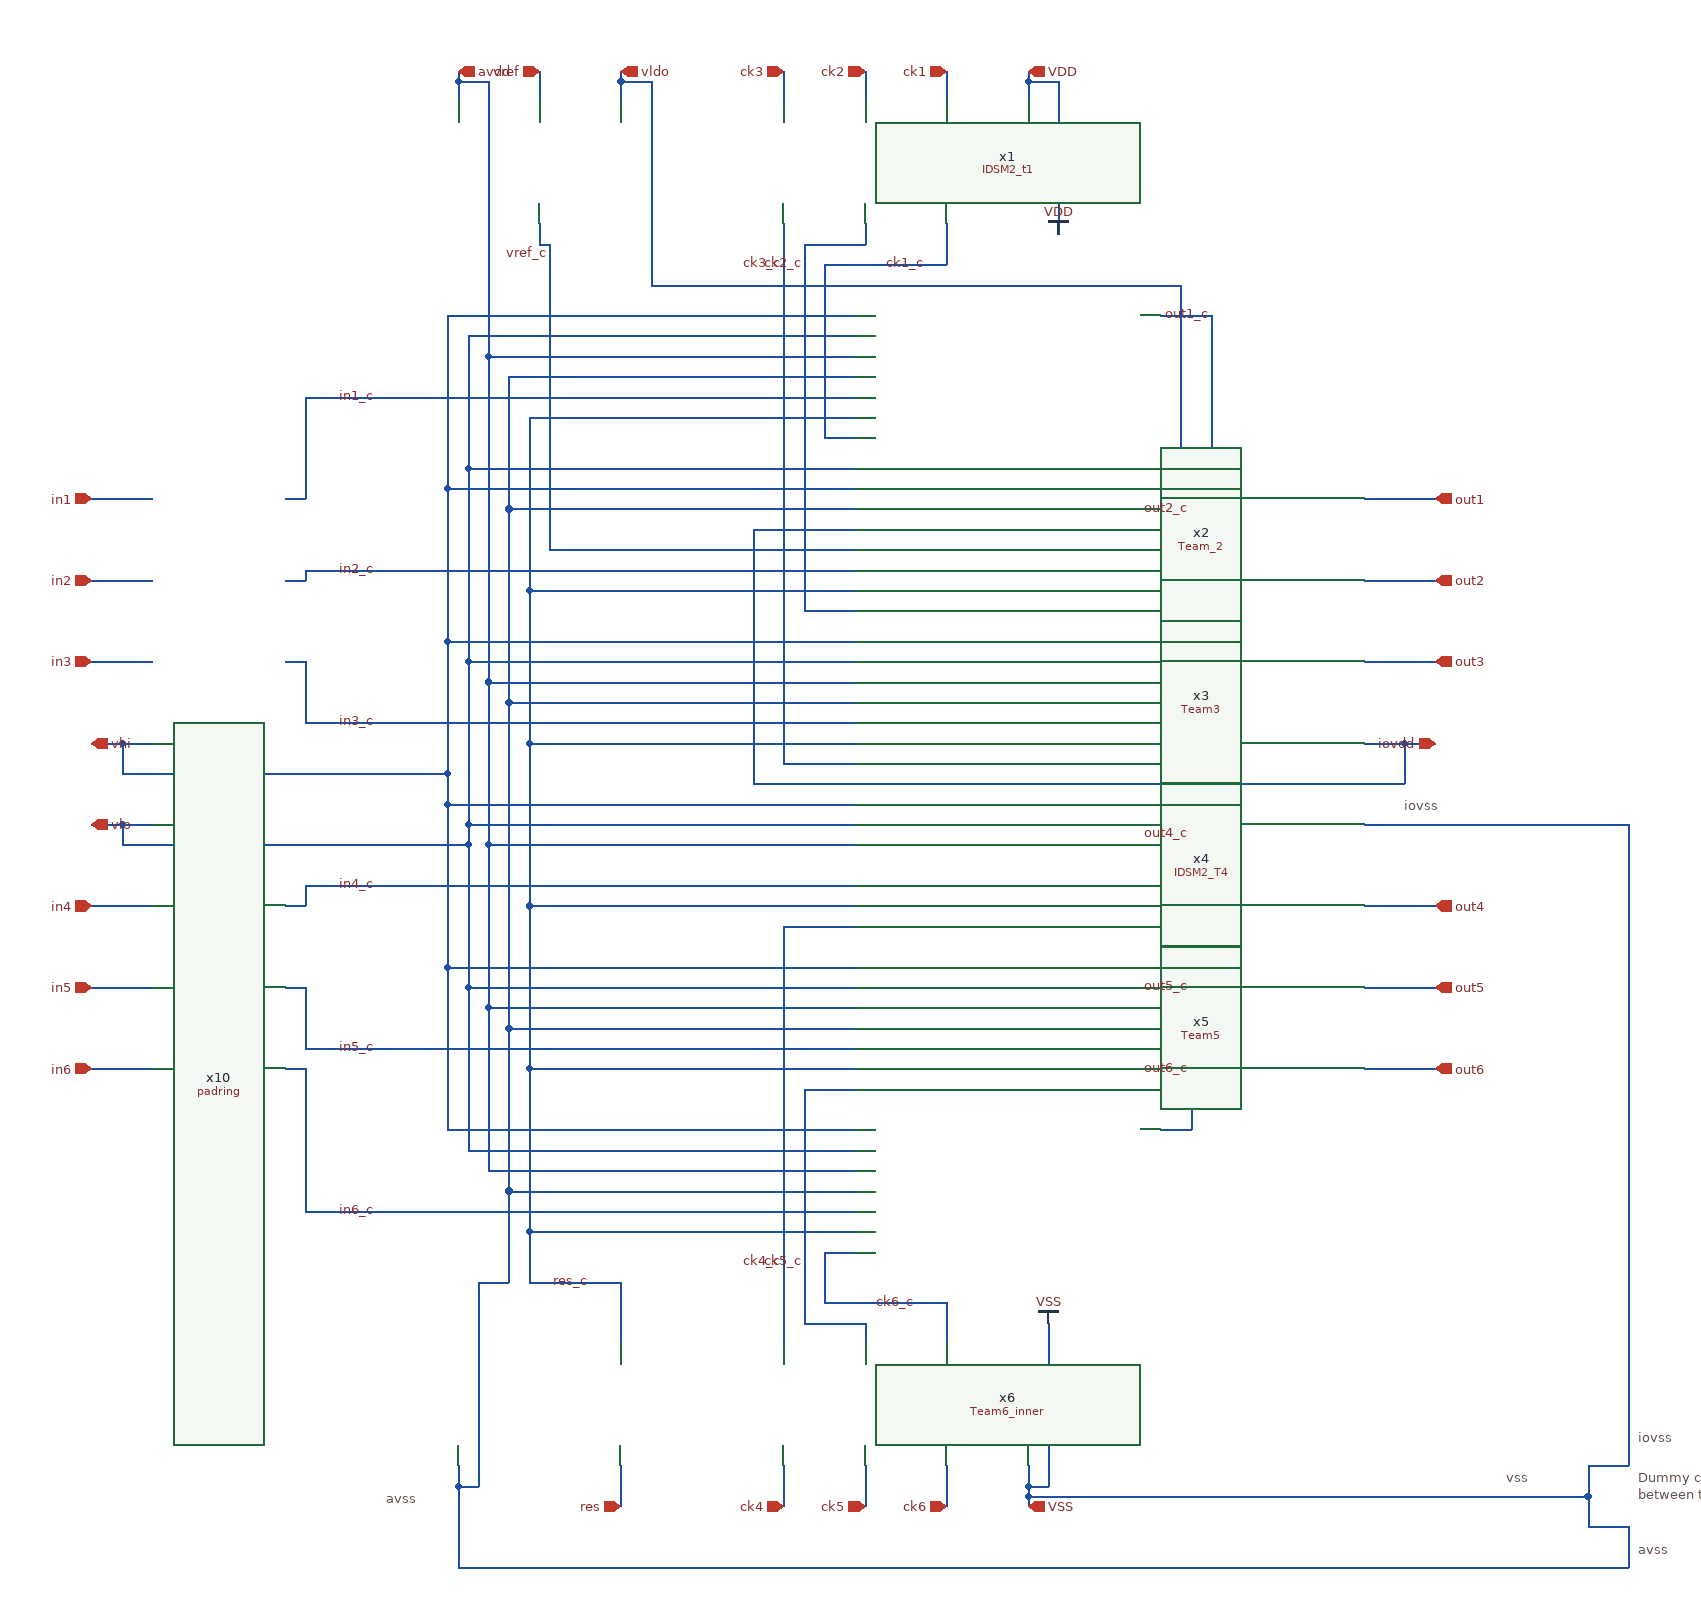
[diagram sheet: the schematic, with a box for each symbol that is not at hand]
v {xschem version=3.4.5 file_version=1.2
}
G {}
K {}
V {}
S {}
E {}
T {avss} 1570 -110 0 0 0.4 0.4 {}
T {iovss} 1340 -840 0 0 0.4 0.4 {}
T {Dummy connections to please LVS (no metal connection 
between these 3 nets, only soft short through substrate)} 1570 -180 0 0 0.4 0.4 {}
T {avss} 340 -160 0 0 0.4 0.4 {}
T {iovss} 1570 -220 0 0 0.4 0.4 {}
T {vss} 1440 -180 0 0 0.4 0.4 {}
N 1150 -1310 1150 -1130 {
lab=out1_c}
N 1130 -1050 1180 -1050 {
lab=out2_c}
N 1150 -970 1180 -970 {
lab=out3_c}
N 1150 -990 1150 -970 {
lab=out3_c}
N 1130 -830 1130 -730 {
lab=out4_c}
N 1130 -730 1180 -730 {
lab=out4_c}
N 1130 -650 1180 -650 {
lab=out5_c}
N 1130 -670 1130 -650 {
lab=out5_c}
N 1130 -570 1130 -510 {
lab=out6_c}
N 1130 -570 1180 -570 {
lab=out6_c}
N 400 -670 400 -510 {
lab=vhi}
N 420 -650 420 -490 {
lab=vlo}
N 440 -630 440 -470 {
lab=avdd}
N 460 -610 460 -450 {
lab=VSS}
N 480 -410 480 -360 {
lab=res_c}
N 80 -890 110 -890 {
lab=vhi}
N 80 -810 110 -810 {
lab=vlo}
N 420 -490 800 -490 {
lab=vlo}
N 400 -510 800 -510 {
lab=vhi}
N 440 -470 800 -470 {
lab=avdd}
N 460 -450 800 -450 {
lab=VSS}
N 410 -160 410 -80 {
lab=VSS}
N 410 -160 430 -160 {
lab=VSS}
N 410 -180 410 -160 {
lab=VSS}
N 430 -360 430 -160 {
lab=VSS}
N 430 -360 460 -360 {
lab=VSS}
N 460 -450 460 -360 {
lab=VSS}
N 570 -360 570 -300 {
lab=res_c}
N 480 -360 570 -360 {
lab=res_c}
N 480 -410 800 -410 {
lab=res_c}
N 480 -570 480 -410 {
lab=res_c}
N 260 -430 800 -430 {
lab=in6_c}
N 260 -570 260 -430 {
lab=in6_c}
N 240 -570 260 -570 {
lab=in6_c}
N 480 -570 800 -570 {
lab=res_c}
N 480 -730 480 -570 {
lab=res_c}
N 460 -610 800 -610 {
lab=VSS}
N 440 -630 800 -630 {
lab=avdd}
N 420 -650 800 -650 {
lab=vlo}
N 400 -670 800 -670 {
lab=vhi}
N 400 -830 400 -670 {
lab=vhi}
N 480 -730 800 -730 {
lab=res_c}
N 440 -790 440 -630 {
lab=avdd}
N 420 -790 420 -650 {
lab=vlo}
N 420 -810 800 -810 {
lab=vlo}
N 440 -790 800 -790 {
lab=avdd}
N 400 -830 800 -830 {
lab=vhi}
N 400 -860 400 -830 {
lab=vhi}
N 80 -790 420 -790 {
lab=vlo}
N 420 -810 420 -790 {
lab=vlo}
N 80 -810 80 -790 {
lab=vlo}
N 260 -590 800 -590 {
lab=in5_c}
N 260 -650 260 -590 {
lab=in5_c}
N 240 -650 260 -650 {
lab=in5_c}
N 260 -750 800 -750 {
lab=in4_c}
N 260 -750 260 -730 {
lab=in4_c}
N 240 -730 260 -730 {
lab=in4_c}
N 480 -890 480 -730 {
lab=res_c}
N 440 -950 440 -790 {
lab=avdd}
N 400 -990 400 -860 {
lab=vhi}
N 480 -1040 480 -890 {
lab=res_c}
N 460 -930 460 -610 {
lab=VSS}
N 440 -1270 440 -950 {
lab=avdd}
N 400 -1140 400 -990 {
lab=vhi}
N 480 -1210 800 -1210 {
lab=res_c}
N 460 -1250 800 -1250 {
lab=VSS}
N 440 -1270 800 -1270 {
lab=avdd}
N 420 -1290 800 -1290 {
lab=vlo}
N 400 -1310 800 -1310 {
lab=vhi}
N 80 -860 400 -860 {
lab=vhi}
N 80 -890 80 -860 {
lab=vhi}
N 240 -970 260 -970 {
lab=in3_c}
N 260 -1060 800 -1060 {
lab=in2_c}
N 260 -1060 260 -1050 {
lab=in2_c}
N 240 -1050 260 -1050 {
lab=in2_c}
N 260 -1230 800 -1230 {
lab=in1_c}
N 260 -1230 260 -1130 {
lab=in1_c}
N 240 -1130 260 -1130 {
lab=in1_c}
N 1100 -1140 1130 -1140 {
lab=out2_c}
N 1100 -990 1150 -990 {
lab=out3_c}
N 1100 -830 1130 -830 {
lab=out4_c}
N 1100 -670 1130 -670 {
lab=out5_c}
N 1100 -510 1130 -510 {
lab=out6_c}
N 730 -710 730 -300 {
lab=ck4_c}
N 730 -710 800 -710 {
lab=ck4_c}
N 750 -550 800 -550 {
lab=ck5_c}
N 750 -550 750 -320 {
lab=ck5_c}
N 750 -320 810 -320 {
lab=ck5_c}
N 810 -320 810 -300 {
lab=ck5_c}
N 890 -340 890 -300 {
lab=ck6_c}
N 770 -340 890 -340 {
lab=ck6_c}
N 770 -390 770 -340 {
lab=ck6_c}
N 770 -390 800 -390 {
lab=ck6_c}
N 730 -870 800 -870 {
lab=ck3_c}
N 730 -1400 730 -870 {
lab=ck3_c}
N 750 -1020 800 -1020 {
lab=ck2_c}
N 750 -1380 750 -1020 {
lab=ck2_c}
N 750 -1380 810 -1380 {
lab=ck2_c}
N 810 -1400 810 -1380 {
lab=ck2_c}
N 770 -1190 800 -1190 {
lab=ck1_c}
N 770 -1360 770 -1190 {
lab=ck1_c}
N 770 -1360 890 -1360 {
lab=ck1_c}
N 890 -1400 890 -1360 {
lab=ck1_c}
N 440 -1540 440 -1270 {
lab=avdd}
N 410 -1540 440 -1540 {
lab=avdd}
N 410 -1540 410 -1520 {
lab=avdd}
N 50 -1130 110 -1130 {
lab=in1}
N 50 -1050 110 -1050 {
lab=in2}
N 50 -970 110 -970 {
lab=in3}
N 50 -730 110 -730 {
lab=in4}
N 50 -650 110 -650 {
lab=in5}
N 50 -570 110 -570 {
lab=in6}
N 50 -890 80 -890 {
lab=vhi}
N 50 -810 80 -810 {
lab=vlo}
N 410 -1550 410 -1540 {
lab=avdd}
N 1300 -1130 1370 -1130 {
lab=out1}
N 1300 -1050 1370 -1050 {
lab=out2}
N 1300 -970 1370 -970 {
lab=out3}
N 1300 -730 1370 -730 {
lab=out4}
N 1300 -650 1370 -650 {
lab=out5}
N 1300 -570 1370 -570 {
lab=out6}
N 1340 -890 1370 -890 {
lab=iovdd}
N 1300 -810 1560 -810 {
lab=VSS}
N 970 -150 970 -140 {
lab=VSS}
N 970 -160 990 -160 {
lab=VSS}
N 970 -180 970 -160 {
lab=VSS}
N 990 -320 990 -160 {
lab=VSS}
N 970 -1540 1000 -1540 {
lab=VDD}
N 970 -1540 970 -1520 {
lab=VDD}
N 970 -1550 970 -1540 {
lab=VDD}
N 1000 -1540 1000 -1390 {
lab=VDD}
N 730 -1550 730 -1520 {
lab=ck3}
N 810 -1550 810 -1520 {
lab=ck2}
N 890 -1550 890 -1520 {
lab=ck1}
N 490 -1550 490 -1520 {
lab=vref}
N 570 -180 570 -140 {
lab=res}
N 730 -180 730 -140 {
lab=ck4}
N 810 -180 810 -140 {
lab=ck5}
N 890 -180 890 -140 {
lab=ck6}
N 1150 -1130 1180 -1130 {
lab=out1_c}
N 1100 -1310 1150 -1310 {
lab=out1_c}
N 400 -990 800 -990 {
lab=vhi}
N 260 -910 800 -910 {
lab=in3_c}
N 260 -970 260 -910 {
lab=in3_c}
N 410 -80 1560 -80 {
lab=VSS}
N 1560 -120 1560 -80 {
lab=VSS}
N 1560 -810 1560 -180 {
lab=VSS}
N 1520 -180 1560 -180 {
lab=VSS}
N 1520 -150 1520 -120 {
lab=VSS}
N 1520 -120 1560 -120 {
lab=VSS}
N 1520 -180 1520 -150 {
lab=VSS}
N 970 -150 1520 -150 {
lab=VSS}
N 970 -160 970 -150 {
lab=VSS}
N 480 -1040 800 -1040 {
lab=res_c}
N 480 -1210 480 -1040 {
lab=res_c}
N 490 -1400 490 -1380 {
lab=vref_c}
N 490 -1380 500 -1380 {
lab=vref_c}
N 500 -1380 500 -1080 {
lab=vref_c}
N 500 -1080 800 -1080 {
lab=vref_c}
N 420 -1160 800 -1160 {
lab=vlo}
N 420 -970 420 -810 {
lab=vlo}
N 420 -1290 420 -1160 {
lab=vlo}
N 400 -1140 800 -1140 {
lab=vhi}
N 400 -1310 400 -1140 {
lab=vhi}
N 460 -930 800 -930 {
lab=VSS}
N 460 -1120 460 -930 {
lab=VSS}
N 480 -890 800 -890 {
lab=res_c}
N 440 -950 800 -950 {
lab=avdd}
N 420 -970 800 -970 {
lab=vlo}
N 420 -1160 420 -970 {
lab=vlo}
N 460 -1120 800 -1120 {
lab=VSS}
N 460 -1250 460 -1120 {
lab=VSS}
N 1130 -1140 1130 -1050 {
lab=out2_c}
N 700 -1100 800 -1100 {
lab=iovdd}
N 700 -1100 700 -850 {
lab=iovdd}
N 700 -850 1340 -850 {
lab=iovdd}
N 1340 -890 1340 -850 {
lab=iovdd}
N 1300 -890 1340 -890 {
lab=iovdd}
N 1100 -1160 1120 -1160 {
lab=vldo}
N 1120 -1340 1120 -1160 {
lab=vldo}
N 600 -1340 1120 -1340 {
lab=vldo}
N 570 -1540 570 -1520 {
lab=vldo}
N 600 -1540 600 -1340 {
lab=vldo}
N 570 -1540 600 -1540 {
lab=vldo}
N 570 -1550 570 -1540 {
lab=vldo}
C {devices/title.sym} 160 -40 0 0 {name=l1 author="Boris Murmann"}
C {padring.sym} 130 -200 0 0 {name=x10}
C {/foss/designs/EE628/5_Design/4_Layout/Team 1/IDSM2_t1.sym} 950 -1250 0 0 {name=x1}
C {/foss/designs/EE628/5_Design/4_Layout/Team 2 - Transformer Monster Tractors/Team_2.sym} 950 -1090 0 0 {name=x2}
C {/foss/designs/EE628/5_Design/4_Layout/Team 4/IDSM2_T4.sym} 950 -770 0 0 {name=x4}
C {/foss/designs/EE628/5_Design/4_Layout/Team 5/Team5.sym} 950 -610 0 0 {name=x5}
C {devices/ipin.sym} 50 -1130 0 0 {name=p1 lab=in1}
C {devices/ipin.sym} 50 -1050 0 0 {name=p2 lab=in2}
C {devices/ipin.sym} 50 -970 0 0 {name=p3 lab=in3}
C {devices/ipin.sym} 50 -730 0 0 {name=p4 lab=in4}
C {devices/ipin.sym} 50 -650 0 0 {name=p5 lab=in5}
C {devices/ipin.sym} 50 -570 0 0 {name=p6 lab=in6}
C {devices/iopin.sym} 1370 -890 0 0 {name=p7 lab=iovdd}
C {devices/iopin.sym} 50 -810 0 1 {name=p8 lab=vlo}
C {devices/iopin.sym} 410 -1550 1 1 {name=p10 lab=avdd}
C {devices/opin.sym} 1370 -1130 0 0 {name=p11 lab=out1}
C {devices/opin.sym} 1370 -1050 0 0 {name=p12 lab=out2}
C {devices/opin.sym} 1370 -970 0 0 {name=p13 lab=out3}
C {devices/opin.sym} 1370 -730 0 0 {name=p14 lab=out4}
C {devices/opin.sym} 1370 -650 0 0 {name=p15 lab=out5}
C {devices/opin.sym} 1370 -570 0 0 {name=p16 lab=out6}
C {devices/iopin.sym} 970 -140 3 1 {name=p18 lab=VSS}
C {devices/vdd.sym} 990 -320 0 0 {name=l2 lab=VSS}
C {devices/iopin.sym} 970 -1550 1 1 {name=p19 lab=VDD}
C {devices/vdd.sym} 1000 -1390 2 0 {name=l3 lab=VDD}
C {devices/iopin.sym} 570 -1550 1 1 {name=p20 lab=vldo}
C {devices/ipin.sym} 730 -1550 1 0 {name=p21 lab=ck3}
C {devices/ipin.sym} 810 -1550 1 0 {name=p22 lab=ck2}
C {devices/ipin.sym} 890 -1550 1 0 {name=p23 lab=ck1}
C {devices/ipin.sym} 490 -1550 1 0 {name=p24 lab=vref}
C {devices/ipin.sym} 570 -140 3 0 {name=p25 lab=res}
C {devices/ipin.sym} 730 -140 3 0 {name=p26 lab=ck4}
C {devices/ipin.sym} 810 -140 3 0 {name=p27 lab=ck5}
C {devices/ipin.sym} 890 -140 3 0 {name=p28 lab=ck6}
C {devices/iopin.sym} 50 -890 0 1 {name=p29 lab=vhi}
C {devices/lab_wire.sym} 540 -360 0 0 {name=p31 sig_type=std_logic lab=res_c}
C {devices/lab_wire.sym} 330 -1230 0 0 {name=p32 sig_type=std_logic lab=in1_c}
C {devices/lab_wire.sym} 330 -1060 0 0 {name=p33 sig_type=std_logic lab=in2_c}
C {devices/lab_wire.sym} 330 -910 0 0 {name=p34 sig_type=std_logic lab=in3_c}
C {devices/lab_wire.sym} 330 -750 0 0 {name=p35 sig_type=std_logic lab=in4_c}
C {devices/lab_wire.sym} 330 -590 0 0 {name=p36 sig_type=std_logic lab=in5_c}
C {devices/lab_wire.sym} 330 -430 0 0 {name=p37 sig_type=std_logic lab=in6_c}
C {devices/lab_wire.sym} 730 -1360 3 0 {name=p38 sig_type=std_logic lab=ck3_c}
C {devices/lab_wire.sym} 750 -1360 3 0 {name=p39 sig_type=std_logic lab=ck2_c}
C {devices/lab_wire.sym} 870 -1360 0 0 {name=p40 sig_type=std_logic lab=ck1_c}
C {devices/lab_wire.sym} 860 -340 0 0 {name=p41 sig_type=std_logic lab=ck6_c}
C {devices/lab_wire.sym} 730 -380 3 0 {name=p42 sig_type=std_logic lab=ck4_c}
C {devices/lab_wire.sym} 750 -380 3 0 {name=p43 sig_type=std_logic lab=ck5_c}
C {devices/lab_wire.sym} 1150 -970 0 0 {name=p44 sig_type=std_logic lab=out3_c}
C {devices/lab_wire.sym} 1150 -1310 0 0 {name=p45 sig_type=std_logic lab=out1_c}
C {devices/lab_wire.sym} 1130 -1120 3 0 {name=p46 sig_type=std_logic lab=out2_c}
C {devices/lab_wire.sym} 1130 -800 3 0 {name=p47 sig_type=std_logic lab=out4_c}
C {devices/lab_wire.sym} 1130 -570 3 0 {name=p48 sig_type=std_logic lab=out6_c}
C {devices/lab_wire.sym} 1130 -650 0 0 {name=p49 sig_type=std_logic lab=out5_c}
C {/foss/designs/EE628/5_Design/4_Layout/Team 6/Team6_inner.sym} 950 -450 0 0 {name=x6}
C {/foss/designs/EE628/5_Design/4_Layout/Team 3/Team3.sym} 950 -930 0 0 {name=x3}
C {devices/lab_wire.sym} 500 -1370 3 0 {name=p9 sig_type=std_logic lab=vref_c}
